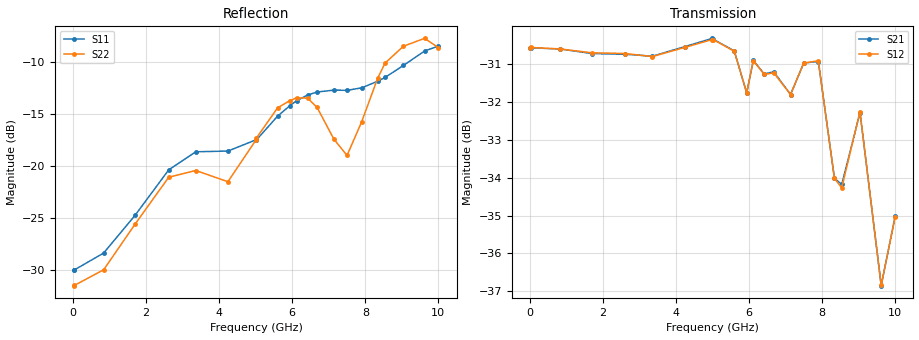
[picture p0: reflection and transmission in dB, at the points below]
! Integrated Device Technology
! Corporate Headquarters
! 6024 Silver Creek Valley Road
! San Jose, CA 95138  USA
! Phone:  1-408-284-8200
! Toll Free:  1-800-223-1366
! Webpage:  http://www.idt.com/
! Timing and RF Division
! 515 Groton Road, Suite 102
! Westford, MA 01886-6024
! Device:  F1958
! Description: 7-bit 0.25 dB Digital Step Attenuator
! Frequency:  0.001 -  6.000 GHz
! Package:  4x4 mm Thin QFN Plastic Package: 24 pin
! Ports:  2 RF, 12 DC
!  Pin  1  = D0
!  Pin  2  = VDD
!  Pin  3  = VMODE
!  Pin  4  = GND
!  Pin  5  = RF1  =  Port 1
!  Pin  6  = GND
!  Pin  7  = GND
!  Pin  8  = GND
!  Pin  9  = GND
!  Pin 10  = GND
!  Pin 11  = GND
!  Pin 12  = GND
!  Pin 13  = GND
!  Pin 14  = RF2  =  Port 2
!  Pin 15  = GND
!  Pin 16  = LE
!  Pin 17  = CLK
!  Pin 18  = DATA
!  Pin 19  = D6
!  Pin 20  = D5
!  Pin 21  = D4
!  Pin 22  = D3
!  Pin 23  = D2
!  Pin 24  = D1
! State:  119
! Atten State:  29.75 dB
! Voltage:  +3.30 Volts
! Current:  0.258 mA
! Data:  The device was measured on a F1958 evaluation board which has
!  individual transmission lines to the RF pins.  Data was collected
!  using a calibrated network analyzer.  The evaluation board was
!  de-embedded using Automatic Fixture Removal (AFR).
!  The reference plane is the edge of the package pin.
! Misc:
!  Action Tracker AT0419
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# GHz S dB R 50
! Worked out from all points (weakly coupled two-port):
!   500 points, 20 MHz to 10 GHz, reference 50 ohm
!   highest |S21| = -30.33 dB at 5 GHz (marker M1); lowest = -36.9 dB at 9.62 GHz (marker M2)
!   lowest |S11| = -30.0 dB at 40 MHz (marker M3), VSWR 1.07, Z = 46.9 - j0.0439 ohm
!   |S11| at or under -10 dB: start of sweep to 9.147 GHz
!   |S22| runs from -31.7 to -7.5 dB; largest |S21 - S12| = 0.00032
!   S11 on the Smith chart (normalised r, x): 20 MHz: 0.94, -0.00; 6.42 GHz: 0.67, +0.17; 10 GHz: 0.67, +0.58
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0.02  -29.97 -178.9  -30.58 -0.2  -30.58 -0.1  -31.52 -179.0
0.04  -30.00 -179.2  -30.58 -0.4  -30.57 -0.4  -31.49 -178.5
0.84  -28.38 170.7  -30.61 -9.5  -30.61 -9.5  -29.99 172.0
1.7  -24.75 170.6  -30.73 -18.7  -30.71 -18.8  -25.60 170.6
2.62  -20.38 176.6  -30.75 -28.8  -30.73 -28.8  -21.09 179.7
3.36  -18.64 -176.0  -30.80 -37.4  -30.81 -37.5  -20.44 -170.2
4.24  -18.57 -179.3  -30.55 -47.0  -30.57 -47.0  -21.52 168.0
5  -17.50 161.3  -30.33 -56.5  -30.36 -56.5  -17.54 136.7
5.02  -17.50 160.5  -30.35 -56.9  -30.36 -56.9  -17.32 137.8
5.6  -15.21 150.6  -30.66 -65.5  -30.67 -65.5  -14.41 139.8
5.94  -14.19 148.2  -31.77 -69.2  -31.77 -69.2  -13.71 148.2
6.12  -13.73 148.6  -30.91 -69.6  -30.92 -69.5  -13.45 151.2
6.42  -13.18 147.6  -31.27 -74.6  -31.28 -74.5  -13.48 156.8
6.68  -12.89 146.7  -31.21 -77.0  -31.24 -77.0  -14.37 157.3
7.14  -12.71 142.9  -31.81 -82.4  -31.81 -82.3  -17.43 151.4
7.5  -12.73 138.4  -30.98 -85.8  -30.98 -85.7  -18.99 119.3
7.9  -12.49 129.1  -30.94 -101.4  -30.92 -101.4  -15.75 89.1
8.34  -11.85 119.1  -34.02 -107.3  -34.02 -107.5  -11.54 83.9
8.54  -11.49 116.1  -34.18 -98.8  -34.27 -98.7  -10.11 86.3
9.04  -10.34 107.1  -32.29 -109.1  -32.26 -109.0  -8.49 97.4
9.62  -8.95 101.6  -36.85 -105.7  -36.84 -105.4  -7.73 111.1
10  -8.47 100.0  -35.02 -88.7  -35.05 -88.5  -8.62 114.0
